One B-rep face of a CAD part: STEP entity #86.
In plain terms, the planar face has unit normal (1, 0, 0).
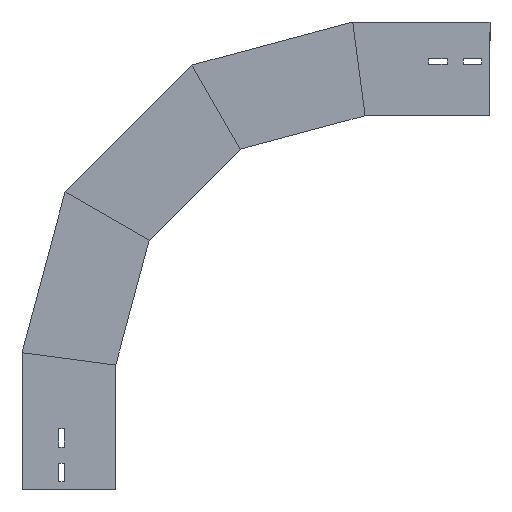
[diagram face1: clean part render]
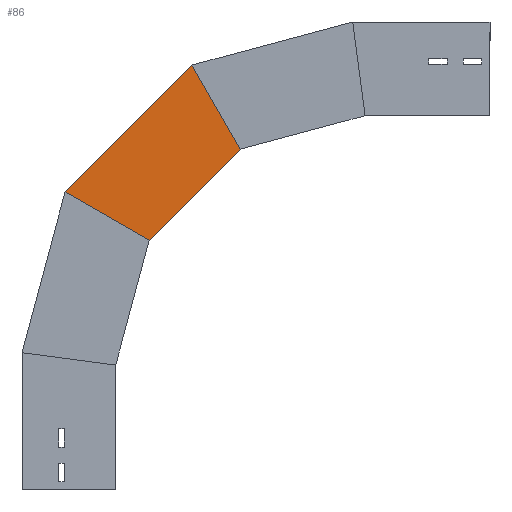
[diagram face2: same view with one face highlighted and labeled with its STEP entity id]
Its self-contained STEP definition (entity closure, numbers rounded to 3 decimals):
#49 = CARTESIAN_POINT ( 'NONE',  ( 0., -40.117, 299.719 ) ) ;
#86 = ADVANCED_FACE ( 'NONE', ( #725 ), #467, .T. ) ;
#170 = EDGE_CURVE ( 'NONE', #1345, #758, #279, .T. ) ;
#209 = CARTESIAN_POINT ( 'NONE',  ( 0., -174.081, 367.123 ) ) ;
#216 = VECTOR ( 'NONE', #652, 1000. ) ;
#222 = ORIENTED_EDGE ( 'NONE', *, *, #383, .T. ) ;
#279 = LINE ( 'NONE', #1015, #1212 ) ;
#383 = EDGE_CURVE ( 'NONE', #1050, #1113, #1328, .T. ) ;
#412 = CARTESIAN_POINT ( 'NONE',  ( 0., -149.719, 409.32 ) ) ;
#467 = PLANE ( 'NONE',  #1421 ) ;
#505 = CARTESIAN_POINT ( 'NONE',  ( 0., -78.533, 277.539 ) ) ;
#638 = VECTOR ( 'NONE', #1619, 1000. ) ;
#651 = EDGE_CURVE ( 'NONE', #1113, #758, #1540, .T. ) ;
#652 = DIRECTION ( 'NONE',  ( 0., -0.5, -0.866 ) ) ;
#723 = CARTESIAN_POINT ( 'NONE',  ( 0., 62.95, 355.751 ) ) ;
#725 = FACE_OUTER_BOUND ( 'NONE', #1407, .T. ) ;
#748 = DIRECTION ( 'NONE',  ( 1., 0., 0. ) ) ;
#758 = VERTEX_POINT ( 'NONE', #412 ) ;
#803 = VECTOR ( 'NONE', #1825, 1000. ) ;
#844 = DIRECTION ( 'NONE',  ( 0., -0.707, 0.707 ) ) ;
#877 = DIRECTION ( 'NONE',  ( 0., 0., -1. ) ) ;
#935 = ORIENTED_EDGE ( 'NONE', *, *, #170, .F. ) ;
#941 = EDGE_CURVE ( 'NONE', #1050, #1345, #1524, .T. ) ;
#974 = CARTESIAN_POINT ( 'NONE',  ( 0., -91.484, 510.185 ) ) ;
#1015 = CARTESIAN_POINT ( 'NONE',  ( 0., -16.599, 276.201 ) ) ;
#1050 = VERTEX_POINT ( 'NONE', #1273 ) ;
#1113 = VERTEX_POINT ( 'NONE', #974 ) ;
#1176 = ORIENTED_EDGE ( 'NONE', *, *, #651, .T. ) ;
#1212 = VECTOR ( 'NONE', #844, 1000. ) ;
#1273 = CARTESIAN_POINT ( 'NONE',  ( 0., 60.748, 357.953 ) ) ;
#1328 = LINE ( 'NONE', #723, #638 ) ;
#1333 = CARTESIAN_POINT ( 'NONE',  ( 0., -16.599, 276.201 ) ) ;
#1345 = VERTEX_POINT ( 'NONE', #49 ) ;
#1374 = ORIENTED_EDGE ( 'NONE', *, *, #941, .F. ) ;
#1407 = EDGE_LOOP ( 'NONE', ( #222, #1176, #935, #1374 ) ) ;
#1421 = AXIS2_PLACEMENT_3D ( 'NONE', #1333, #748, #877 ) ;
#1524 = LINE ( 'NONE', #505, #803 ) ;
#1540 = LINE ( 'NONE', #209, #216 ) ;
#1619 = DIRECTION ( 'NONE',  ( 0., -0.707, 0.707 ) ) ;
#1825 = DIRECTION ( 'NONE',  ( 0., -0.866, -0.5 ) ) ;
